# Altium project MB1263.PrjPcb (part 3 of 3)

## Sheet Power_MPU.SchDoc: Power_MPU
size A3; CompanyName: STMicroelectronics; DocumentNumber: MB1263; Revision: C-04; SheetNumber: 4; SheetTotal: 11; Project: STM32MP157-EVAL

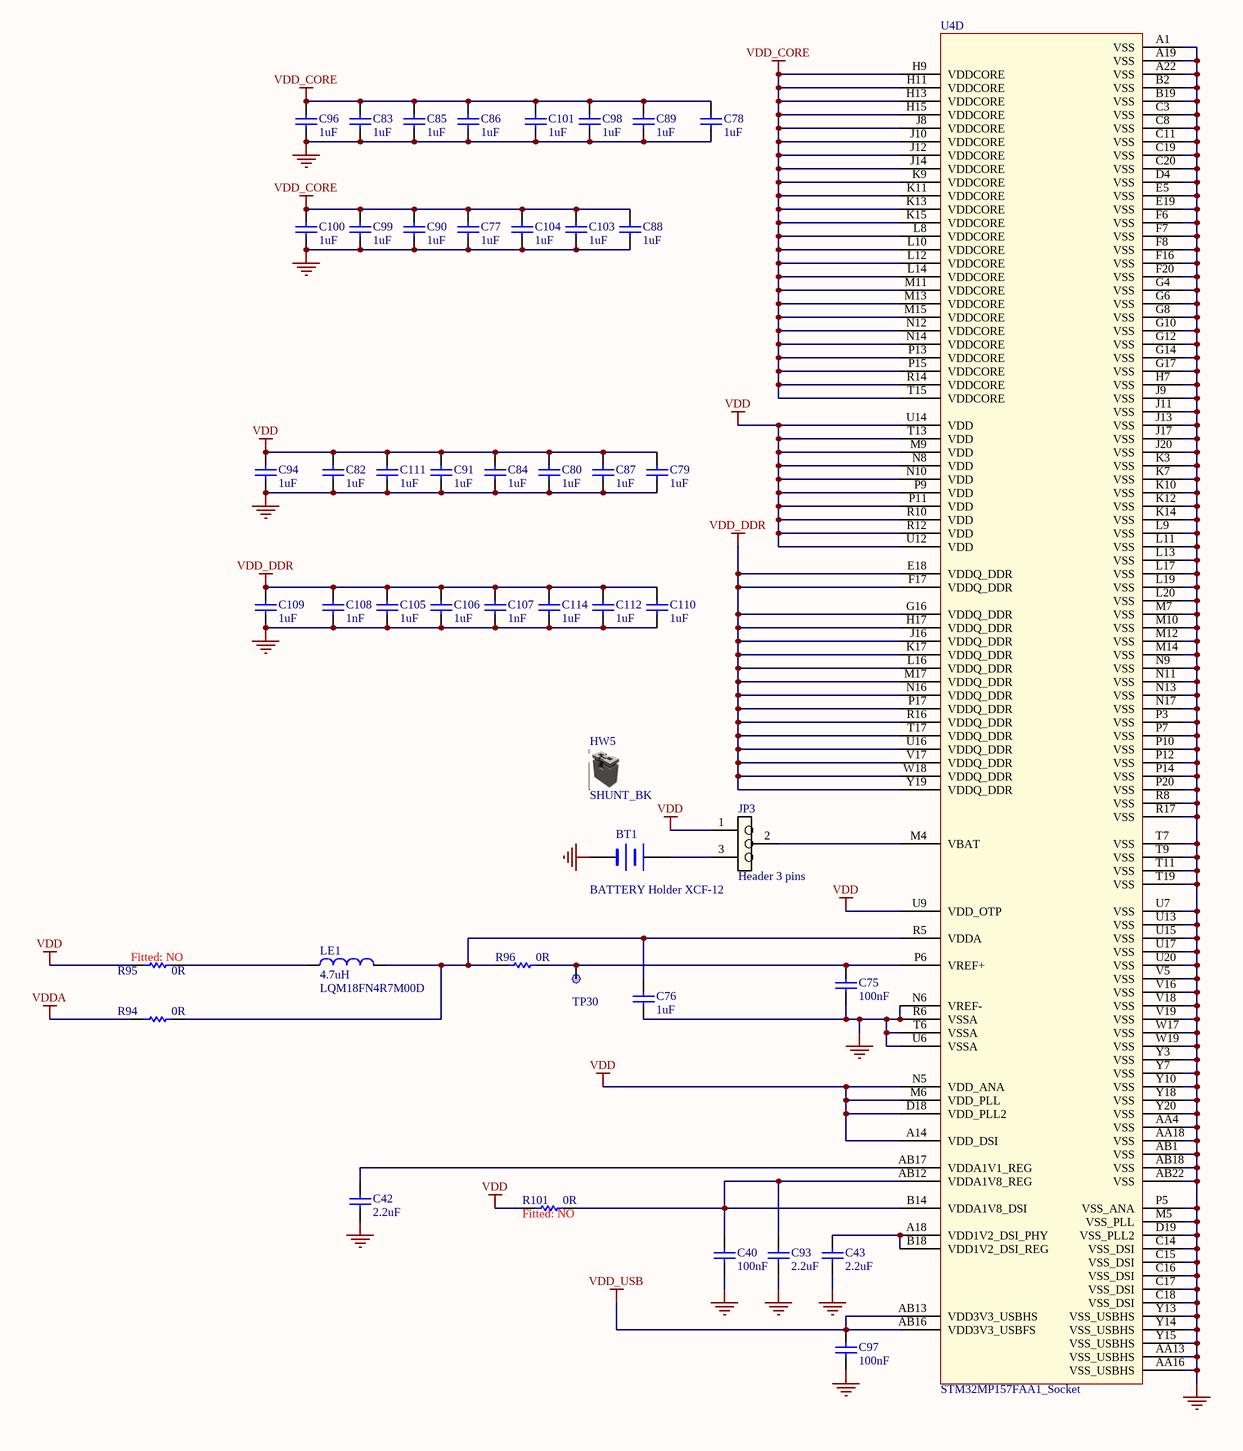
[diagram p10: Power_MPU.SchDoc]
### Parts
BT1  BATTERY Holder XCF-12  [BAT_CHINA_XCF-12_SMD_2P]
C40  100nF  [C0402]
C42  2.2uF  [C0402]
C43  2.2uF  [C0402]
C75  100nF  [C0402]
C76  1uF  [C0603]
C77  1uF  [C0402]
C78  1uF  [C0402]
C79  1uF  [C0402]
C80  1uF  [C0402]
C82  1uF  [C0402]
C83  1uF  [C0402]
C84  1uF  [C0402]
C85  1uF  [C0402]
C86  1uF  [C0402]
C87  1uF  [C0402]
C88  1uF  [C0402]
C89  1uF  [C0402]
C90  1uF  [C0402]
C91  1uF  [C0402]
C93  2.2uF  [C0402]
C94  1uF  [C0402]
C96  1uF  [C0402]
C97  100nF  [C0402]
C98  1uF  [C0402]
C99  1uF  [C0402]
C100  1uF  [C0402]
C101  1uF  [C0402]
C103  1uF  [C0402]
C104  1uF  [C0402]
C105  1uF  [C0402]
C106  1uF  [C0402]
C107  1nF  [C0402]
C108  1nF  [C0402]
C109  1uF  [C0402]
C110  1uF  [C0402]
C111  1uF  [C0402]
C112  1uF  [C0402]
C114  1uF  [C0402]
HW5  SHUNT_BK  (mechanical)
JP3  Header 3 pins  [CON_SAMTEC_TSW-103-07-F-S]
LE1  Manuf_Part_1: LQM18FN4R7M00D  [L0603]  (hidden comment: 4.7uH)
R94  0R  [R0402]
R95  0R  Fitted: NO  [R0402]
R96  0R  [R0402]
R101  0R  Fitted: NO  [R0402]
TP30  TP  [TP_SMD_1MM]  (value not drawn)  (no BOM)
U4  STM32MP157FAA1_Socket  [ICC_LFBGA448_18X18_STM32MP157BAA3_P080__SOCKET_IE_CS1627194MF]  (part D of 5)

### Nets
GND: BT1.2(-) C40.1 C42.1 C43.1 C75.1 C76.1 C77.1 C78.1 C79.1 C80.1 C82.1 C83.1 C84.1 C85.1 C86.1 C87.1 C88.1 C89.1 C90.1 C91.1 C93.1 C94.1 C96.1 C97.1 C98.1 C99.1 C100.1 C101.1 C103.1 C104.1 C105.1 C106.1 C107.1 C108.1 C109.1 C110.1 C111.1 C112.1 C114.1 U4.A1(VSS) U4.A19(VSS) U4.A22(VSS) U4.AA4(VSS) U4.AA13(VSS_USBHS) U4.AA16(VSS_USBHS) U4.AA18(VSS) U4.AB1(VSS) U4.AB18(VSS) U4.AB22(VSS) U4.B2(VSS) U4.B19(VSS) U4.C3(VSS) U4.C8(VSS) U4.C11(VSS) U4.C14(VSS_DSI) U4.C15(VSS_DSI) U4.C16(VSS_DSI) U4.C17(VSS_DSI) U4.C18(VSS_DSI) U4.C19(VSS) U4.C20(VSS) U4.D4(VSS) U4.D19(VSS_PLL2) U4.E5(VSS) U4.E19(VSS) U4.F6(VSS) U4.F7(VSS) U4.F8(VSS) U4.F16(VSS) U4.F20(VSS) U4.G4(VSS) U4.G6(VSS) U4.G8(VSS) U4.G10(VSS) U4.G12(VSS) U4.G14(VSS) U4.G17(VSS) U4.H7(VSS) U4.J9(VSS) U4.J11(VSS) U4.J13(VSS) U4.J17(VSS) U4.J20(VSS) U4.K3(VSS) U4.K7(VSS) U4.K10(VSS) U4.K12(VSS) U4.K14(VSS) U4.L9(VSS) U4.L11(VSS) U4.L13(VSS) U4.L17(VSS) U4.L19(VSS) U4.L20(VSS) U4.M5(VSS_PLL) U4.M7(VSS) U4.M10(VSS) U4.M12(VSS) U4.M14(VSS) U4.N6(VREF-) U4.N9(VSS) U4.N11(VSS) U4.N13(VSS) U4.N17(VSS) U4.P3(VSS) U4.P5(VSS_ANA) U4.P7(VSS) U4.P10(VSS) U4.P12(VSS) U4.P14(VSS) U4.P20(VSS) U4.R6(VSSA) U4.R8(VSS) U4.R17(VSS) U4.T6(VSSA) U4.T7(VSS) U4.T9(VSS) U4.T11(VSS) U4.T19(VSS) U4.U6(VSSA) U4.U7(VSS) U4.U13(VSS) U4.U15(VSS) U4.U17(VSS) U4.U20(VSS) U4.V5(VSS) U4.V16(VSS) U4.V18(VSS) U4.V19(VSS) U4.W17(VSS) U4.W19(VSS) U4.Y3(VSS) U4.Y7(VSS) U4.Y10(VSS) U4.Y13(VSS_USBHS) U4.Y14(VSS_USBHS) U4.Y15(VSS_USBHS) U4.Y18(VSS) U4.Y20(VSS)
VDD: C79.2 C80.2 C82.2 C84.2 C87.2 C91.2 C94.2 C111.2 JP3.1 R95.1 R101.1 U4.A14(VDD_DSI) U4.D18(VDD_PLL2) U4.M6(VDD_PLL) U4.M9(VDD) U4.N5(VDD_ANA) U4.N8(VDD) U4.N10(VDD) U4.P9(VDD) U4.P11(VDD) U4.R10(VDD) U4.R12(VDD) U4.T13(VDD) U4.U9(VDD_OTP) U4.U12(VDD) U4.U14(VDD)
VDD_CORE: C77.2 C78.2 C83.2 C85.2 C86.2 C88.2 C89.2 C90.2 C96.2 C98.2 C99.2 C100.2 C101.2 C103.2 C104.2 U4.H9(VDDCORE) U4.H11(VDDCORE) U4.H13(VDDCORE) U4.H15(VDDCORE) U4.J8(VDDCORE) U4.J10(VDDCORE) U4.J12(VDDCORE) U4.J14(VDDCORE) U4.K9(VDDCORE) U4.K11(VDDCORE) U4.K13(VDDCORE) U4.K15(VDDCORE) U4.L8(VDDCORE) U4.L10(VDDCORE) U4.L12(VDDCORE) U4.L14(VDDCORE) U4.M11(VDDCORE) U4.M13(VDDCORE) U4.M15(VDDCORE) U4.N12(VDDCORE) U4.N14(VDDCORE) U4.P13(VDDCORE) U4.P15(VDDCORE) U4.R14(VDDCORE) U4.T15(VDDCORE)
VDD_DDR: C105.2 C106.2 C107.2 C108.2 C109.2 C110.2 C112.2 C114.2 U4.E18(VDDQ_DDR) U4.F17(VDDQ_DDR) U4.G16(VDDQ_DDR) U4.H17(VDDQ_DDR) U4.J16(VDDQ_DDR) U4.K17(VDDQ_DDR) U4.L16(VDDQ_DDR) U4.M17(VDDQ_DDR) U4.N16(VDDQ_DDR) U4.P17(VDDQ_DDR) U4.R16(VDDQ_DDR) U4.T17(VDDQ_DDR) U4.U16(VDDQ_DDR) U4.V17(VDDQ_DDR) U4.W18(VDDQ_DDR) U4.Y19(VDDQ_DDR)
VDD_USB: C97.2 U4.AB13(VDD3V3_USBHS) U4.AB16(VDD3V3_USBFS)
VDDA: R94.1
NetBT1_1: BT1.1(+) JP3.3
NetC40_2: C40.2 C93.2 R101.2 U4.AB12(VDDA1V8_REG) U4.B14(VDDA1V8_DSI)
NetC42_2: C42.2 U4.AB17(VDDA1V1_REG)
NetC43_2: C43.2 U4.A18(VDD1V2_DSI_PHY) U4.B18(VDD1V2_DSI_REG)
NetC75_2: C75.2 R96.2 TP30.1 U4.P6(VREF+)
NetC76_2: C76.2 LE1.2 R94.2 R96.1 U4.R5(VDDA)
NetJP3_2: JP3.2 U4.M4(VBAT)
NetLE1_1: LE1.1 R95.2

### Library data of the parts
BT1 = BATTERY Holder XCF-12: Battery  holder xcfbattery XCF-12; Fitted: YES; Ordered_By: Subcon
C40 C75 C97 = Cap_100nF_X7R_10%_0402: Capacitor,100nF,16V,X7R,10%,0402,YAGEO; Manuf_Part_1: CC0402KRX7R7BB104; Fitted: YES; Ordered_By: Subcon
C42 C43 C93 = Cap_2.2uF_X5R_10%_6V3_0402: Capacitor,MLCC,2.2uF,6V3,X5R,10%,0402,T=0.5; Manuf_Part_1: GRM155R60J225KE95D; Manuf_1: MURATA; Fitted: YES; Ordered_By: Subcon
C76 = Cap_1uF_X5R_10%_0603: Capacitor,1uF,16V,X5R,10%,0603,YAGEO; Manuf_Part_1: CC0603KRX5R7BB105; Fitted: YES; Ordered_By: Subcon
C77-C80 C82-C91 C94 C96 C98-C101 C103-C106 C109-C112 C114 = Cap_1uF_X5R_10%_6V3_0402: Capacitor MLCC 1µF 10% 6,3V 0,4uF@3,3V X5R 0402 MURATA; Manuf_Part_1: GRM155R61E105KA12; Fitted: YES; Ordered_By: Subcon
C107 C108 = Cap_1nF_X7R_10%_0402: Capacitor,1nF,16V,X7R,10%,0402,YAGEO; Manuf_Part_1: CC0402KRX7R7BB102; Order_Code: 1816754; Fitted: YES; Ordered_By: Subcon
HW5 = Shunt 2.54mm: SHUNT 2.54mm BLACK; Manuf_1: SAMTEC; Manuf_Part_1: SNT-100-BK-G; Fitted: YES; Ordered_By: Subcon
JP3 = Header 3: Header, 3-Pin; Manuf_1: Samtec; Manuf_Part_1: TSW-103-07-F-S; Fitted: YES; Ordered_By: Subcon
LE1 = IND_4.7uH 600mohm_80mA_0603: IND 4.7µH 20% 80mA 600mhom 0603; Manuf_1: MURATA; Ordered_By: Subcon; Fitted: YES
R94 R96 = Res_0_5%_0402: Resistor,0R,0402,5%,YAGEO; Manuf_Part_1: RC0402JR-070RL; Order_Code: 2363467; Fitted: YES; Ordered_By: Subcon
R95 R101 = Res_0_5%_0402: Resistor,0R,0402,5%,YAGEO; Manuf_Part_1: RC0402JR-070RL; Order_Code: 2363467; Ordered_By: Subcon
TP30 = TP 1mm: Test Point; Fitted: YES
U4 = STM32MP157FAA1_Socket: MPU LFBGA18x18 with crypto-Increased Frequency; Manuf_1: ST; Fitted: YES; Ordered_By: Subcon

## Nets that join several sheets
1V8: Power_PMIC (R76.2), Samtec Connectors QTH_North_South (CN7.2 CN7.4)
2V8: Power_PMIC (R75.2), Samtec Connectors QTH_North_South (CN8.2 CN8.4 CN8.6 CN8.8)
3V3: eMMC (6 pins), Power_PMIC (R61.1 R62.1 R87.2 U3.27), Peripherals (R3.1 R4.2), ST_LINK_V2-1 (R90.1), Samtec Connectors QTH_North_South (CN8.1 CN8.3 CN8.5 CN8.7)
GND: eMMC (17 pins), DDR3_2x16bits (91 pins), Power_PMIC (43 pins), MPU_18x18 (15 pins), SD3 card (13 pins), Peripherals (19 pins), ST_LINK_V2-1 (38 pins), Samtec Connectors QTH_North_South (40 pins), Power_MPU (139 pins)
VBUS_OTG: Power_PMIC (R85.2), Samtec Connectors QTH_North_South (CN8.11 CN8.13 CN8.15)
VBUS_SW: Power_PMIC (R84.2), Samtec Connectors QTH_North_South (CN8.19 CN8.21 CN8.23)
VDD: eMMC (11 pins), Power_PMIC (R15.2 R64.1 R82.2 U3.31), MPU_18x18 (10 pins), SD3 card (6 pins), Peripherals (R8.2 R11.1 R12.1 R13.1), Samtec Connectors QTH_North_South (CN7.8 CN7.10), Power_MPU (26 pins)
VDD_CORE: Power_PMIC (LNK1.2 R81.2), Power_MPU (40 pins)
VDD_DDR: DDR3_2x16bits (58 pins), Power_PMIC (LNK2.2 R79.1 R80.2), Power_MPU (24 pins)
VDD_SD: Power_PMIC (R77.2), SD3 card (5 pins)
VDD_USB: Power_PMIC (R83.2), Power_MPU (C97.2 U4.AB13 U4.AB16)
VDDA: Power_PMIC (R86.2), Power_MPU (R94.1)
VIN: Power_PMIC (15 pins), ST_LINK_V2-1 (D3.1 D5.1), Samtec Connectors QTH_North_South (CN7.7 CN7.9 CN7.11)
VREF_DDR: DDR3_2x16bits (8 pins), Power_PMIC (C19.2 U3.16), MPU_18x18 (C113.2 U4.AB19)
VTT_DDR: DDR3_2x16bits (39 pins), Power_PMIC (R78.2)
ADC118_DAC1: MPU_18x18 (U4.V6), Peripherals (R24.1)
ADC119_DAC2: MPU_18x18 (U4.U5), Peripherals (R25.1)
ANA0: MPU_18x18 (U4.R4), Peripherals (R22.1)
ANA0_MB: Peripherals (SB6.2), Samtec Connectors QTH_North_South (CN8.10)
ANA1: MPU_18x18 (U4.T5), Peripherals (R23.1)
ANA1_MB: Peripherals (SB7.2), Samtec Connectors QTH_North_South (CN8.12)
BOOT0: MPU_18x18 (U4.N3), Peripherals (CN3.2 SW1.8)
BOOT1: MPU_18x18 (U4.N4), Peripherals (CN3.4 SW1.7)
BOOT2: MPU_18x18 (U4.P4), Peripherals (CN3.6 SW1.6)
CAN1_RX: MPU_18x18 (U4.J5), Samtec Connectors QTH_North_South (CN7.97)
CAN1_TX: MPU_18x18 (U4.D3), Samtec Connectors QTH_North_South (CN7.95)
CAN_FD_STBY: MPU_18x18 (U4.U4), Samtec Connectors QTH_North_South (CN8.39)
DCMI_D0: MPU_18x18 (U4.E6), Samtec Connectors QTH_North_South (CN7.68)
DCMI_D1: MPU_18x18 (U4.B1), Samtec Connectors QTH_North_South (CN7.71)
DCMI_D2: MPU_18x18 (U4.B3), Samtec Connectors QTH_North_South (CN7.73)
DCMI_D3: MPU_18x18 (U4.F5), Samtec Connectors QTH_North_South (CN7.64)
DCMI_D4: MPU_18x18 (U4.C2), Samtec Connectors QTH_North_South (CN7.61)
DCMI_D5: MPU_18x18 (U4.J6), Samtec Connectors QTH_North_South (CN7.66)
DCMI_D6: MPU_18x18 (U4.AB8), Samtec Connectors QTH_North_South (CN7.69)
DCMI_D7: MPU_18x18 (U4.E9), Samtec Connectors QTH_North_South (CN7.72)
DCMI_D8: MPU_18x18 (U4.E2), Samtec Connectors QTH_North_South (CN7.62)
DCMI_D9: MPU_18x18 (U4.W2), Samtec Connectors QTH_North_South (CN7.65)
DCMI_D10: MPU_18x18 (U4.E3), Samtec Connectors QTH_North_South (CN7.63)
DCMI_D11: MPU_18x18 (U4.C1), Samtec Connectors QTH_North_South (CN7.75)
DCMI_HSYNC: MPU_18x18 (U4.D6), Samtec Connectors QTH_North_South (CN7.70)
DCMI_PIXCK: MPU_18x18 (U4.W9), Samtec Connectors QTH_North_South (CN7.67)
DCMI_VSYNC: MPU_18x18 (U4.F11), Samtec Connectors QTH_North_South (CN7.74)
DDR_A0: DDR3_2x16bits (R128.1 U6.N3 U7.N3), MPU_18x18 (U4.K19)
DDR_A1: DDR3_2x16bits (R116.1 U6.P7 U7.P7), MPU_18x18 (U4.M18)
DDR_A2: DDR3_2x16bits (R126.1 TP32.1 U6.P3 U7.P3), MPU_18x18 (U4.J18)
DDR_A3: DDR3_2x16bits (R127.1 U6.N2 U7.N2), MPU_18x18 (U4.J19)
DDR_A4: DDR3_2x16bits (R106.1 U6.P8 U7.P8), MPU_18x18 (U4.T18)
DDR_A5: DDR3_2x16bits (R125.1 U6.P2 U7.P2), MPU_18x18 (U4.H19)
DDR_A6: DDR3_2x16bits (R105.1 U6.R8 U7.R8), MPU_18x18 (U4.U19)
DDR_A7: DDR3_2x16bits (R122.1 U6.R2 U7.R2), MPU_18x18 (U4.F18)
DDR_A8: DDR3_2x16bits (R104.1 U6.T8 U7.T8), MPU_18x18 (U4.U18)
DDR_A9: DDR3_2x16bits (R124.1 U6.R3 U7.R3), MPU_18x18 (U4.H18)
DDR_A10: DDR3_2x16bits (R114.1 U6.L7 U7.L7), MPU_18x18 (U4.N18)
DDR_A11: DDR3_2x16bits (R112.1 U6.R7 U7.R7), MPU_18x18 (U4.P19)
DDR_A12: DDR3_2x16bits (R117.1 U6.N7 U7.N7), MPU_18x18 (U4.N19)
DDR_A13: DDR3_2x16bits (R123.1 U6.T3 U7.T3), MPU_18x18 (U4.G18)
DDR_A14: DDR3_2x16bits (R110.1 U6.T7 U7.T7), MPU_18x18 (U4.P18)
DDR_A15: DDR3_2x16bits (R119.1 U6.M7 U7.M7), MPU_18x18 (U4.M19)
DDR_BA0: DDR3_2x16bits (R129.1 U6.M2 U7.M2), MPU_18x18 (U4.K20)
DDR_BA1: DDR3_2x16bits (R107.1 U6.N8 U7.N8), MPU_18x18 (U4.R18)
DDR_BA2: DDR3_2x16bits (R130.1 U6.M3 U7.M3), MPU_18x18 (U4.K18)
DDR_CASN: DDR3_2x16bits (R134.1 TP33.1 U6.K3 U7.K3), MPU_18x18 (U4.M22)
DDR_CKE: DDR3_2x16bits (R108.2 R109.1 U6.K9 U7.K9), MPU_18x18 (U4.R19)
DDR_CLK_N: DDR3_2x16bits (R118.2 U6.K7 U7.K7), MPU_18x18 (U4.N21)
DDR_CLK_P: DDR3_2x16bits (R118.1 U6.J7 U7.J7), MPU_18x18 (U4.N20)
DDR_CSN: DDR3_2x16bits (R132.1 U6.L2 U7.L2), MPU_18x18 (U4.L18)
DDR_DQ0: DDR3_2x16bits (TP22.1 U6.D7), MPU_18x18 (U4.E21)
DDR_DQ1: DDR3_2x16bits (U6.A7), MPU_18x18 (U4.F21)
DDR_DQ2: DDR3_2x16bits (U6.A3), MPU_18x18 (U4.H21)
DDR_DQ3: DDR3_2x16bits (U6.B8), MPU_18x18 (U4.E20)
DDR_DQ4: DDR3_2x16bits (U6.C3), MPU_18x18 (U4.J21)
DDR_DQ5: DDR3_2x16bits (U6.C2), MPU_18x18 (U4.H20)
DDR_DQ6: DDR3_2x16bits (U6.A2), MPU_18x18 (U4.H22)
DDR_DQ7: DDR3_2x16bits (U6.C8), MPU_18x18 (U4.G19)
DDR_DQ8: DDR3_2x16bits (U6.E3), MPU_18x18 (U4.N22)
DDR_DQ9: DDR3_2x16bits (U6.H3), MPU_18x18 (U4.R21)
DDR_DQ10: DDR3_2x16bits (U6.F2), MPU_18x18 (U4.P21)
DDR_DQ11: DDR3_2x16bits (U6.F7), MPU_18x18 (U4.T20)
DDR_DQ12: DDR3_2x16bits (U6.H7), MPU_18x18 (U4.V20)
DDR_DQ13: DDR3_2x16bits (U6.G2), MPU_18x18 (U4.R20)
DDR_DQ14: DDR3_2x16bits (U6.F8), MPU_18x18 (U4.U21)
DDR_DQ15: DDR3_2x16bits (U6.H8), MPU_18x18 (U4.V21)
DDR_DQ16: DDR3_2x16bits (U7.D7), MPU_18x18 (U4.B21)
DDR_DQ17: DDR3_2x16bits (U7.A2), MPU_18x18 (U4.D21)
DDR_DQ18: DDR3_2x16bits (U7.A3), MPU_18x18 (U4.D22)
DDR_DQ19: DDR3_2x16bits (U7.B8), MPU_18x18 (U4.B20)
DDR_DQ20: DDR3_2x16bits (U7.C8), MPU_18x18 (U4.A20)
DDR_DQ21: DDR3_2x16bits (TP25.1 U7.C3), MPU_18x18 (U4.E22)
DDR_DQ22: DDR3_2x16bits (U7.C2), MPU_18x18 (U4.D20)
DDR_DQ23: DDR3_2x16bits (U7.A7), MPU_18x18 (U4.A21)
DDR_DQ24: DDR3_2x16bits (U7.E3), MPU_18x18 (U4.V22)
DDR_DQ25: DDR3_2x16bits (U7.F2), MPU_18x18 (U4.W20)
DDR_DQ26: DDR3_2x16bits (U7.F8), MPU_18x18 (U4.AB21)
DDR_DQ27: DDR3_2x16bits (U7.H8), MPU_18x18 (U4.AB20)
DDR_DQ28: DDR3_2x16bits (U7.F7), MPU_18x18 (U4.AA21)
DDR_DQ29: DDR3_2x16bits (U7.H7), MPU_18x18 (U4.AA20)
DDR_DQ30: DDR3_2x16bits (U7.G2), MPU_18x18 (U4.W22)
DDR_DQ31: DDR3_2x16bits (U7.H3), MPU_18x18 (U4.W21)
DDR_DQM0: DDR3_2x16bits (U6.D3), MPU_18x18 (U4.G20)
DDR_DQM1: DDR3_2x16bits (U6.E7), MPU_18x18 (U4.T21)
DDR_DQM2: DDR3_2x16bits (U7.D3), MPU_18x18 (U4.C22)
DDR_DQM3: DDR3_2x16bits (U7.E7), MPU_18x18 (U4.AA22)
DDR_DQS0_N: DDR3_2x16bits (TP21.1 U6.B7), MPU_18x18 (U4.G21)
DDR_DQS0_P: DDR3_2x16bits (TP20.1 U6.C7), MPU_18x18 (U4.G22)
DDR_DQS1_N: DDR3_2x16bits (U6.G3), MPU_18x18 (U4.R22)
DDR_DQS1_P: DDR3_2x16bits (U6.F3), MPU_18x18 (U4.T22)
DDR_DQS2_N: DDR3_2x16bits (TP27.1 U7.B7), MPU_18x18 (U4.B22)
DDR_DQS2_P: DDR3_2x16bits (TP28.1 U7.C7), MPU_18x18 (U4.C21)
DDR_DQS3_N: DDR3_2x16bits (U7.G3), MPU_18x18 (U4.Y22)
DDR_DQS3_P: DDR3_2x16bits (U7.F3), MPU_18x18 (U4.Y21)
DDR_ODT: DDR3_2x16bits (R131.1 U6.K1 U7.K1), MPU_18x18 (U4.L21)
DDR_RASN: DDR3_2x16bits (R120.1 TP34.1 U6.J3 U7.J3), MPU_18x18 (U4.M20)
DDR_RESETN: DDR3_2x16bits (R103.2 U6.T2 U7.T2), MPU_18x18 (U4.F19)
DDR_WEN: DDR3_2x16bits (R133.1 TP36.1 U6.L3 U7.L3), MPU_18x18 (U4.M21)
DFSDM_CKOUT: MPU_18x18 (U4.V10), Samtec Connectors QTH_North_South (CN8.63)
DFSDM_DATA1: MPU_18x18 (U4.U3), Samtec Connectors QTH_North_South (CN8.26)
DFSDM_DATA3: MPU_18x18 (U4.W7), Samtec Connectors QTH_North_South (CN8.65)
DFSDM_DATA5: MPU_18x18 (U4.E4), Samtec Connectors QTH_North_South (CN7.20)
DSI_CK_N: MPU_18x18 (U4.A16), Samtec Connectors QTH_North_South (CN7.107)
DSI_CK_P: MPU_18x18 (U4.B16), Samtec Connectors QTH_North_South (CN7.109)
DSI_D0_N: MPU_18x18 (U4.A15), Samtec Connectors QTH_North_South (CN7.103)
DSI_D0_P: MPU_18x18 (U4.B15), Samtec Connectors QTH_North_South (CN7.105)
DSI_D1_N: MPU_18x18 (U4.A17), Samtec Connectors QTH_North_South (CN7.113)
DSI_D1_P: MPU_18x18 (U4.B17), Samtec Connectors QTH_North_South (CN7.111)
DSI_RESET: MPU_18x18 (U4.W6), Samtec Connectors QTH_North_South (CN8.59)
DSI_TE: MPU_18x18 (U4.E13), Samtec Connectors QTH_North_South (CN7.117)
ETH_CLK125: MPU_18x18 (U4.U8), Samtec Connectors QTH_North_South (CN8.51)
ETH_GTX_CLK: MPU_18x18 (U4.AB4), Samtec Connectors QTH_North_South (CN8.46)
ETH_MDC: MPU_18x18 (U4.AB3), Samtec Connectors QTH_North_South (CN8.38)
ETH_MDINT: MPU_18x18 (U4.W5), Samtec Connectors QTH_North_South (CN8.47)
ETH_MDIO: MPU_18x18 (U4.AB2), Samtec Connectors QTH_North_South (CN8.36)
ETH_RX_CLK: MPU_18x18 (U4.V4), Samtec Connectors QTH_North_South (CN8.42)
ETH_RX_DV: MPU_18x18 (U4.Y9), Samtec Connectors QTH_North_South (CN8.60)
ETH_RXD0: MPU_18x18 (U4.AB6), Samtec Connectors QTH_North_South (CN8.58)
ETH_RXD1: MPU_18x18 (U4.AA6), Samtec Connectors QTH_North_South (CN8.56)
ETH_RXD2: MPU_18x18 (U4.AB5), Samtec Connectors QTH_North_South (CN8.54)
ETH_RXD3: MPU_18x18 (U4.AA5), Samtec Connectors QTH_North_South (CN8.52)
ETH_TX_EN: MPU_18x18 (U4.Y5), Samtec Connectors QTH_North_South (CN8.50)
ETH_TXD0: MPU_18x18 (U4.AA1), Samtec Connectors QTH_North_South (CN8.34)
ETH_TXD1: MPU_18x18 (U4.AA2), Samtec Connectors QTH_North_South (CN8.32)
ETH_TXD2: MPU_18x18 (U4.Y1), Samtec Connectors QTH_North_South (CN8.30)
ETH_TXD3: MPU_18x18 (U4.Y2), Samtec Connectors QTH_North_South (CN8.28)
GPIO7: MPU_18x18 (U4.V3), Samtec Connectors QTH_North_South (CN8.41)
HDMI_CEC: MPU_18x18 (U4.E11), Samtec Connectors QTH_North_South (CN7.93)
I2C2_SCL: MPU_18x18 (R31.1 U4.A3), Samtec Connectors QTH_North_South (CN7.79)
I2C2_SDA: MPU_18x18 (R30.1 U4.A2), Samtec Connectors QTH_North_South (CN7.78)
I2C4_SCL: Power_PMIC (CN5.2 U3.4), MPU_18x18 (R53.2 U4.G1)
I2C4_SDA: Power_PMIC (CN5.4 U3.3), MPU_18x18 (R93.2 U4.H4)
I2C5_SCL: MPU_18x18 (R34.1 U4.Y16), Samtec Connectors QTH_North_South (CN8.105)
I2C5_SDA: MPU_18x18 (R35.1 U4.W16), Samtec Connectors QTH_North_South (CN8.107)
JTCK_SWCLK: MPU_18x18 (U4.D17), Samtec Connectors QTH_North_South (CN7.100)
JTDI: MPU_18x18 (U4.D16), Samtec Connectors QTH_North_South (CN7.98)
JTDO_TRACESWO: MPU_18x18 (U4.E16), Samtec Connectors QTH_North_South (CN7.104)
JTMS_SWDIO: MPU_18x18 (U4.E17), Samtec Connectors QTH_North_South (CN7.106)
LCD_BL_CTRL: MPU_18x18 (U4.V14), Samtec Connectors QTH_North_South (CN8.111)
LED_B: MPU_18x18 (U4.M2), Peripherals (R5.1)
LED_Y: MPU_18x18 (U4.M1), Peripherals (R6.1)
LTDC_B0: MPU_18x18 (U4.B8), Samtec Connectors QTH_North_South (CN7.57)
LTDC_B1: MPU_18x18 (U4.A7), Samtec Connectors QTH_North_South (CN7.54)
LTDC_B2: MPU_18x18 (U4.B7), Samtec Connectors QTH_North_South (CN7.56)
LTDC_B3: MPU_18x18 (U4.C7), Samtec Connectors QTH_North_South (CN7.55)
LTDC_B4: MPU_18x18 (U4.B6), Samtec Connectors QTH_North_South (CN7.51)
LTDC_B5: MPU_18x18 (U4.A6), Samtec Connectors QTH_North_South (CN7.52)
LTDC_B6: MPU_18x18 (U4.C6), Samtec Connectors QTH_North_South (CN7.53)
LTDC_B7: MPU_18x18 (U4.A5), Samtec Connectors QTH_North_South (CN7.50)
LTDC_CLK: MPU_18x18 (U4.D2), Samtec Connectors QTH_North_South (CN7.36)
LTDC_DE: MPU_18x18 (U4.B5), Samtec Connectors QTH_North_South (CN7.49)
LTDC_G0: MPU_18x18 (U4.L4), Samtec Connectors QTH_North_South (CN7.43)
LTDC_G1: MPU_18x18 (U4.H6), Samtec Connectors QTH_North_South (CN7.41)
LTDC_G2: MPU_18x18 (U4.L2), Samtec Connectors QTH_North_South (CN7.37)
LTDC_G3: MPU_18x18 (U4.J3), Samtec Connectors QTH_North_South (CN7.42)
LTDC_G4: MPU_18x18 (U4.K6), Samtec Connectors QTH_North_South (CN7.48)
LTDC_G5: MPU_18x18 (U4.D8), Samtec Connectors QTH_North_South (CN7.60)
LTDC_G6: MPU_18x18 (U4.E7), Samtec Connectors QTH_North_South (CN7.58)
LTDC_G7: MPU_18x18 (U4.E8), Samtec Connectors QTH_North_South (CN7.59)
LTDC_HSYNC: MPU_18x18 (U4.H2), Samtec Connectors QTH_North_South (CN7.33)
LTDC_R0: MPU_18x18 (U4.F3), Samtec Connectors QTH_North_South (CN7.47)
LTDC_R1: MPU_18x18 (U4.J2), Samtec Connectors QTH_North_South (CN7.39)
LTDC_R2: MPU_18x18 (U4.L6), Samtec Connectors QTH_North_South (CN7.46)
LTDC_R3: MPU_18x18 (U4.K4), Samtec Connectors QTH_North_South (CN7.44)
LTDC_R4: MPU_18x18 (U4.J1), Samtec Connectors QTH_North_South (CN7.35)
LTDC_R5: MPU_18x18 (U4.K2), Samtec Connectors QTH_North_South (CN7.40)
LTDC_R6: MPU_18x18 (U4.K1), Samtec Connectors QTH_North_South (CN7.38)
LTDC_R7: MPU_18x18 (U4.L5), Samtec Connectors QTH_North_South (CN7.45)
LTDC_VSYNC: MPU_18x18 (U4.H1), Samtec Connectors QTH_North_South (CN7.34)
MCO1: MPU_18x18 (TP7.1 U4.T3), Samtec Connectors QTH_North_South (CN8.33)
MCO2: MPU_18x18 (TP8.1 U4.W4), Samtec Connectors QTH_North_South (CN8.43)
NAND_ALE: MPU_18x18 (U4.W12), Samtec Connectors QTH_North_South (CN8.101)
NAND_CLE: MPU_18x18 (U4.AB9), Samtec Connectors QTH_North_South (CN8.89)
NAND_D0: MPU_18x18 (U4.M3), Samtec Connectors QTH_North_South (CN8.87)
NAND_D1: MPU_18x18 (U4.L1), Samtec Connectors QTH_North_South (CN8.81)
NAND_D2: MPU_18x18 (U4.C10), Samtec Connectors QTH_North_South (CN7.29)
NAND_D3: MPU_18x18 (U4.B10), Samtec Connectors QTH_North_South (CN7.27)
NAND_D4: MPU_18x18 (U4.W10), Samtec Connectors QTH_North_South (CN8.91)
NAND_D5: MPU_18x18 (U4.Y12), Samtec Connectors QTH_North_South (CN8.95)
NAND_D6: MPU_18x18 (U4.W11), Samtec Connectors QTH_North_South (CN8.93)
NAND_D7: MPU_18x18 (U4.W14), Samtec Connectors QTH_North_South (CN8.99)
NAND_NCE: MPU_18x18 (U4.W15), Samtec Connectors QTH_North_South (CN8.97)
NAND_NOE: MPU_18x18 (U4.C9), Samtec Connectors QTH_North_South (CN7.30)
NAND_NWAIT: MPU_18x18 (U4.L3), Samtec Connectors QTH_North_South (CN7.24)
NAND_NWE: MPU_18x18 (U4.A9), Samtec Connectors QTH_North_South (CN7.28)
NJTRST: MPU_18x18 (U4.E15), Samtec Connectors QTH_North_South (CN7.102)
NRST: Power_PMIC (U3.1), MPU_18x18 (R27.2 U4.R2), SD3 card (D2.2), Peripherals (5 pins), Samtec Connectors QTH_North_South (CN7.17)
OTG_ID: MPU_18x18 (U4.Y17), Samtec Connectors QTH_North_South (CN8.98)
OTG_VBUS: MPU_18x18 (U4.V15), Samtec Connectors QTH_North_South (CN8.100)
PA0_WKUP: Power_PMIC (U3.43), MPU_18x18 (U4.AA3), Samtec Connectors QTH_North_South (CN7.15)
PA13: MPU_18x18 (U4.W3), Peripherals (B2.1 B2.2 JP6.1 LD2.2), Samtec Connectors QTH_North_South (CN8.25)
PA14: MPU_18x18 (U4.R3), Peripherals (B3.1 B3.2 LD3.2 TP1.1), Samtec Connectors QTH_North_South (CN8.27)
PF12: MPU_18x18 (U4.V8), Peripherals (R21.1)
PF12_MB: Peripherals (SB5.2), Samtec Connectors QTH_North_South (CN8.57)
PMIC_WAKEUP: Power_PMIC (U3.2), MPU_18x18 (TP5.1 U4.N2)
QSPI_BK1_IO0: MPU_18x18 (U4.AB10), Samtec Connectors QTH_North_South (CN8.76)
QSPI_BK1_IO1: MPU_18x18 (U4.AB11), Samtec Connectors QTH_North_South (CN8.78)
QSPI_BK1_IO2: MPU_18x18 (U4.AA10), Samtec Connectors QTH_North_South (CN8.80)
QSPI_BK1_IO3: MPU_18x18 (U4.AA11), Samtec Connectors QTH_North_South (CN8.82)
QSPI_BK1_NCS: MPU_18x18 (U4.W13), Samtec Connectors QTH_North_South (CN8.74)
QSPI_BK2_IO0: MPU_18x18 (U4.AB7), Samtec Connectors QTH_North_South (CN8.64)
QSPI_BK2_IO1: MPU_18x18 (U4.Y6), Samtec Connectors QTH_North_South (CN8.66)
QSPI_BK2_IO2: MPU_18x18 (U4.AA9), Samtec Connectors QTH_North_South (CN8.68)
QSPI_BK2_IO3: MPU_18x18 (U4.Y11), Samtec Connectors QTH_North_South (CN8.70)
QSPI_BK2_NCS: MPU_18x18 (U4.U10), Samtec Connectors QTH_North_South (CN8.72)
QSPI_CLK: MPU_18x18 (U4.V12), Samtec Connectors QTH_North_South (CN8.62)
SAI2_FSA: MPU_18x18 (U4.F1), Samtec Connectors QTH_North_South (CN7.112)
SAI2_FSB: MPU_18x18 (U4.A4), Samtec Connectors QTH_North_South (CN7.14)
SAI2_MCLKA: MPU_18x18 (U4.C5), Samtec Connectors QTH_North_South (CN7.110)
SAI2_MCLKB: MPU_18x18 (U4.B4), Samtec Connectors QTH_North_South (CN7.16)
SAI2_SCKA: MPU_18x18 (U4.F2), Samtec Connectors QTH_North_South (CN7.114)
SAI2_SDA: MPU_18x18 (U4.G5), Samtec Connectors QTH_North_South (CN7.118)
SAI2_SDB: MPU_18x18 (U4.W8), Samtec Connectors QTH_North_South (CN7.116)
SDMMC1_CDIR: MPU_18x18 (U4.F12), SD3 card (M1.24 R37.2 R38.1)
SDMMC1_CK: MPU_18x18 (U4.E12), SD3 card (R42.1)
SDMMC1_CKIN: MPU_18x18 (U4.F15), SD3 card (M1.10)
SDMMC1_CMD: MPU_18x18 (U4.D12), SD3 card (M1.7)
SDMMC1_D0: MPU_18x18 (U4.E14), SD3 card (M1.6)
SDMMC1_D0DIR: MPU_18x18 (U4.F13), SD3 card (M1.23 R39.1 R40.2)
SDMMC1_D1: MPU_18x18 (U4.D14), SD3 card (M1.8)
SDMMC1_D2: MPU_18x18 (U4.F14), SD3 card (M1.2)
SDMMC1_D3: MPU_18x18 (U4.D15), SD3 card (M1.3)
SDMMC1_D123DIR: MPU_18x18 (U4.D13), SD3 card (M1.11 R48.2 R49.1)
SDMMC3_CK: MPU_18x18 (U4.D10), Samtec Connectors QTH_North_South (CN7.89)
SDMMC3_CMD: MPU_18x18 (U4.B9), Samtec Connectors QTH_North_South (CN7.80)
SDMMC3_D0: MPU_18x18 (U4.E10), Samtec Connectors QTH_North_South (CN7.91)
SDMMC3_D1: MPU_18x18 (U4.F9), Samtec Connectors QTH_North_South (CN7.87)
SDMMC3_D2: MPU_18x18 (U4.D9), Samtec Connectors QTH_North_South (CN7.86)
SDMMC3_D3: MPU_18x18 (U4.F10), Samtec Connectors QTH_North_South (CN7.88)
SPDIF_RX: MPU_18x18 (U4.J4), Samtec Connectors QTH_North_South (CN7.120)
SPDIF_TX: MPU_18x18 (U4.AA8), Samtec Connectors QTH_North_South (CN8.75)
SPI1_MISO: MPU_18x18 (U4.H5), Samtec Connectors QTH_North_South (CN7.84)
SPI1_MOSI: MPU_18x18 (U4.K5), Samtec Connectors QTH_North_South (CN7.82)
SPI1_NSS: MPU_18x18 (U4.F4), Samtec Connectors QTH_North_South (CN7.85)
SPI1_SCK: MPU_18x18 (U4.G2), Samtec Connectors QTH_North_South (CN7.83)
SUB_NRST: MPU_18x18 (R97.1 U4.A8), Samtec Connectors QTH_North_South (CN7.26)
TIM2_CH4: MPU_18x18 (U4.T4), Samtec Connectors QTH_North_South (CN8.37)
TIM8_CH4: MPU_18x18 (U4.E1), Samtec Connectors QTH_North_South (CN7.81)
TIM12_CH1: MPU_18x18 (U4.V11), Samtec Connectors QTH_North_South (CN8.77)
UART4_TX: MPU_18x18 (U4.U11), Peripherals (JP6.2)
USART1_CK: MPU_18x18 (U4.G3), Samtec Connectors QTH_North_South (CN8.20)
USART1_TX: MPU_18x18 (U4.H3), Samtec Connectors QTH_North_South (CN8.22)
USART3_CTS: MPU_18x18 (U4.W1), Samtec Connectors QTH_North_South (CN8.31)
USART3_RTS: MPU_18x18 (U4.Y8), Samtec Connectors QTH_North_South (CN8.69)
USART3_RX: MPU_18x18 (U4.AA7), Samtec Connectors QTH_North_South (CN8.71)
USART3_TX: MPU_18x18 (U4.V9), Samtec Connectors QTH_North_South (CN8.61)
USB1_N: MPU_18x18 (U4.AB15), Samtec Connectors QTH_North_South (CN8.94)
USB1_P: MPU_18x18 (U4.AA15), Samtec Connectors QTH_North_South (CN8.92)
USB2_N: MPU_18x18 (U4.AA14), Samtec Connectors QTH_North_South (CN8.86)
USB2_P: MPU_18x18 (U4.AB14), Samtec Connectors QTH_North_South (CN8.88)
uSD_DETECT: MPU_18x18 (U4.Y4), SD3 card (CN9.10 M1.9)
uSD_LDO_SEL: MPU_18x18 (U4.V7), SD3 card (M1.1 R41.2)
uSD_LS_EN: MPU_18x18 (U4.D5), SD3 card (R45.1)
